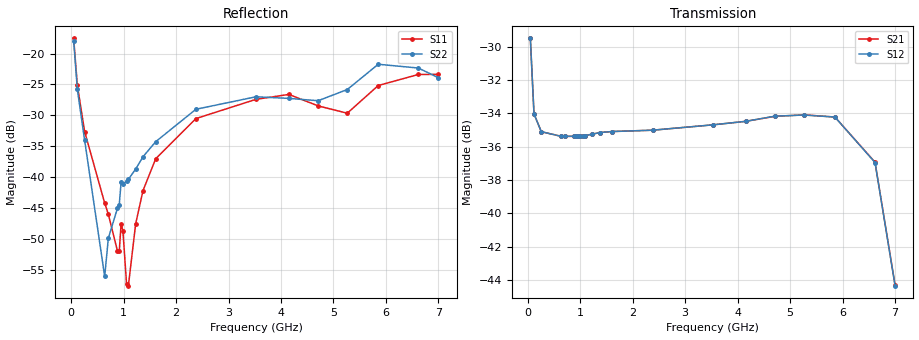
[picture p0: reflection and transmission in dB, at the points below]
! Integrated Device Technology
! Corporate Headquarters
! 6024 Silver Creek Valley Road
! San Jose, CA 95138  USA
! Phone:  1-408-284-8200
! Toll Free:  1-800-223-1366
! Webpage:  http://www.idt.com/
! Timing and RF Division
! 515 Groton Road, Suite 102
! Westford, MA 01886-6024
! Device:  F2258
! Description: Voltage Variable RF Attenuator
! Frequency:  50.0 -  6000.00 MHz
! Package:  3x3 mm Thin QFN Plastic Package: 16 pin
! Ports:  2 RF, 2 DC
!  Pin  1  = NC
!  Pin  2  = NC
!  Pin  3  = RF2  = Port 2
!  Pin  4  = GND
!  Pin  5  = Vdd
!  Pin  6  = NC
!  Pin  7  = VCTRL
!  Pin  8  = NC
!  Pin  9  = GND
!  Pin 10  = RF1  = Port 1
!  Pin 11  = NC
!  Pin 12  = NC
!  Pin 13  = NC
!  Pin 14  = NC
!  Pin 15  = NC
!  Pin 16  = NC
! Vcntrl:  2.210 Volts
! Vdd:  +3.300 Volts
! Current:  1.150 mA
! Data:  The device was measured on a the F2258 evaluation board which has
!  individual transmission lines to the RF pins.  Data was collected
!  using a calibrated network analyzer.  The evaluation board was
!  de-embedded using a TRL calibration technique.
!  The reference plane is the edge of the package pin.
! Misc:  SN 10
!  Action Tracker AT0285
! Date Measured:  2014-12-10
! Date:  2016-01-13  MJV
! Note:
!  Integrated Device Technology supplies this data as a sample of measured
!  data at the package pin for this product.  Your particular data for this
!  product may vary.
!  Data was taken at 25 degrees C.
!  Integrated Device Technology reserves the right to change this data at anytime.
!Freq_(GHz)  S11M_(dB)  S11P_(deg)  S21M_(dB)  S21P_(deg)  S12M_(dB)  S12P_(deg)  S22M_(dB)  S22P_(deg)
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# GHz S dB R 50
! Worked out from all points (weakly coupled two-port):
!   201 points, 50 MHz to 7 GHz, reference 50 ohm
!   highest |S21| = -29.50 dB at 50 MHz (marker M1); lowest = -44.3 dB at 7 GHz (marker M2)
!   lowest |S11| = -57.6 dB at 1.093 GHz (marker M3), VSWR 1.00, Z = 49.9 + j0.115 ohm
!   |S11| at or under -10 dB: start of sweep to end of sweep
!   |S22| runs from -56.1 to -17.9 dB; largest |S21 - S12| = 6.8e-05
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0.05  -17.55 -111.0  -29.50 -68.2  -29.50 -68.2  -17.93 -111.0
0.1195  -25.12 -106.9  -34.03 -36.8  -34.03 -36.8  -25.79 -105.5
0.2585  -32.62 -111.8  -35.10 -18.7  -35.10 -18.8  -34.02 -108.8
0.64075  -44.20 -128.0  -35.38 -9.7  -35.38 -9.7  -56.07 163.7
0.71025  -46.00 -137.7  -35.38 -9.2  -35.38 -9.2  -49.89 116.9
0.884  -51.95 166.3  -35.38 -8.4  -35.37 -8.4  -45.03 104.6
0.91875  -52.01 150.6  -35.38 -8.4  -35.37 -8.4  -44.44 103.2
0.9535  -47.52 -162.7  -35.38 -8.3  -35.38 -8.3  -40.82 114.5
0.98825  -48.68 -174.5  -35.37 -8.1  -35.36 -8.1  -41.09 111.7
1.05775  -57.31 156.5  -35.35 -8.0  -35.34 -8.0  -40.65 96.0
1.0925  -57.56 119.9  -35.33 -8.0  -35.33 -7.9  -40.35 92.2
1.2315  -47.54 47.3  -35.25 -8.0  -35.25 -8.0  -38.69 71.6
1.3705  -42.19 37.0  -35.15 -8.4  -35.15 -8.4  -36.70 60.3
1.61375  -37.01 32.8  -35.09 -9.7  -35.09 -9.7  -34.26 48.7
2.37825  -30.53 48.2  -35.01 -13.3  -35.01 -13.3  -29.02 40.8
3.525  -27.41 91.6  -34.69 -19.8  -34.69 -19.8  -27.00 65.7
4.1505  -26.62 105.0  -34.48 -24.2  -34.48 -24.2  -27.26 73.8
4.7065  -28.47 95.6  -34.18 -28.9  -34.17 -28.9  -27.64 57.1
5.2625  -29.66 54.3  -34.09 -35.0  -34.10 -35.0  -25.83 19.6
5.85325  -25.18 29.9  -34.22 -45.6  -34.22 -45.6  -21.74 -3.5
6.61775  -23.39 49.7  -36.93 -68.7  -36.95 -68.7  -22.35 -45.2
7  -23.38 84.5  -44.31 -61.8  -44.34 -61.3  -23.92 -129.7
